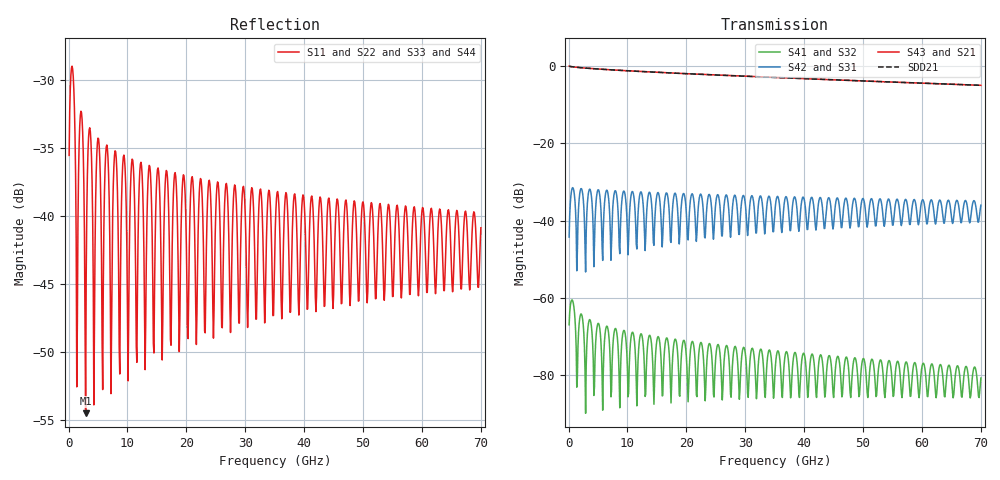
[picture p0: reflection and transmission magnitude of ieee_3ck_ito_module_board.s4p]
! IEEE P802.3ck contribution ito_3ck_01_1118 (Nov 2018): module compliance board PCB trace model,
! decimated 10:1 in frequency by SerDes Optical Lab PRO for use as a measurement fixture (de-embedding).
! Source: https://www.ieee802.org/3/ck/public/tools/c2m/ito_3ck_01_1118_PCBtrace.zip (Module_Board.s4p)
! Original SHA-256: 860cce7cbf4f86d31035675fff817a0d373664c1019b068fa99dbd4dd2adf08a
! AWR Design Environment (8415) Thu Oct 18 13:44:33 2018
# HZ S DB R 50
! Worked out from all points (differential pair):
!   700 points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, 100 MHz to 70 GHz, reference 50 ohm
!   strongest paths, dB at 100 MHz, 17.6 GHz, 35.1 GHz, 52.6 GHz, 70 GHz:
!     S43: -0.1, -1.9, -3.0, -4.1, -5.0
!     S21: -0.1, -1.9, -3.0, -4.1, -5.0
!     S42: -44.3, -38.3, -36.4, -35.6, -36.0
!     S31: -44.3, -38.3, -36.4, -35.6, -36.0
!     S41: -66.9, -77.6, -77.9, -78.6, -80.7
!     S32: -66.9, -77.6, -77.9, -78.6, -80.7
!   taken as a pair (ports 3,1 in; 4,2 out), SDD21 dB: -0.1, -1.9, -3.0, -4.1, -5.0
!   lowest |S11| = -54.5 dB at 2.9 GHz (marker M1), VSWR 1.00, Z = 50.2 + j0.0529 ohm
!   |S11| at or under -10 dB: start of sweep to end of sweep
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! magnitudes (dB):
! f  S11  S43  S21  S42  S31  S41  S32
! 100 MHz  -35.5  -0.1  -0.1  -44.3  -44.3  -66.9  -66.9
! 2.2 GHz  -32.4  -0.5  -0.5  -31.7  -31.7  -64.2  -64.2
! 2.9 GHz  -54.5  -0.6  -0.6  -53.3  -53.3  -89.8  -89.8
! 3.6 GHz  -33.5  -0.7  -0.7  -31.9  -31.9  -65.6  -65.6
! 7.2 GHz  -53.1  -1.0  -1.0  -50.3  -50.3  -85.5  -85.5
! 7.9 GHz  -35.2  -1.1  -1.1  -32.3  -32.3  -67.9  -67.9
! 70 GHz  -40.9  -5.0  -5.0  -36.0  -36.0  -80.7  -80.7
